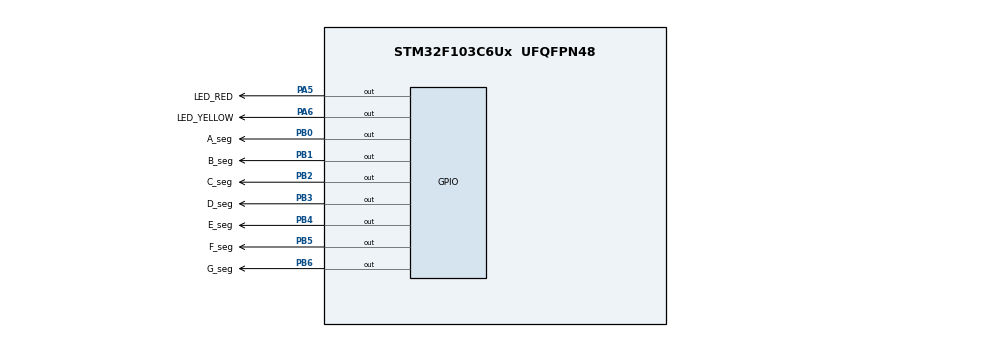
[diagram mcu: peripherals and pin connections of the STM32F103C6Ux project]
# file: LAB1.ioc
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Mcu.Family=STM32F1
Mcu.Name=STM32F103C6Ux
Mcu.Package=UFQFPN48
NVIC.PriorityGroup=NVIC_PRIORITYGROUP_4
PA5.GPIO_Label=LED_RED
PA5.Signal=GPIO_Output
PA6.GPIO_Label=LED_YELLOW
PA6.Signal=GPIO_Output
PB0.GPIO_Label=A_seg
PB0.Signal=GPIO_Output
PB1.GPIO_Label=B_seg
PB1.Signal=GPIO_Output
PB2.GPIO_Label=C_seg
PB2.Signal=GPIO_Output
PB3.GPIO_Label=D_seg
PB3.Signal=GPIO_Output
PB4.GPIO_Label=E_seg
PB4.Signal=GPIO_Output
PB5.GPIO_Label=F_seg
PB5.Signal=GPIO_Output
PB6.GPIO_Label=G_seg
PB6.Signal=GPIO_Output
ProjectManager.HeapSize=0x200
ProjectManager.StackSize=0x400
ProjectManager.TargetToolchain=STM32CubeIDE
RCC.APB1Freq_Value=8000000
RCC.APB2Freq_Value=8000000
VP_SYS_VS_ND.Mode=No_Debug
board=custom

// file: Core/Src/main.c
/* USER CODE BEGIN Header */
/**
  ******************************************************************************
  * @file           : main.c
  * @brief          : Main program body
  ******************************************************************************
  * @attention
  *
  * <h2><center>&copy; Copyright (c) 2023 STMicroelectronics.
  * All rights reserved.</center></h2>
  *
  * This software component is licensed by ST under BSD 3-Clause license,
  * the "License"; You may not use this file except in compliance with the
  * License. You may obtain a copy of the License at:
  *                        opensource.org/licenses/BSD-3-Clause
  *
  ******************************************************************************
  */
/* USER CODE END Header */
#include "main.h"

void SystemClock_Config(void);
static void MX_GPIO_Init(void);
/* USER CODE BEGIN PFP */
void setNumberOnClock(int counter,
		GPIO_TypeDef* C1_GPIO_Post, uint16_t C1_GPIO_Pin,
		GPIO_TypeDef* C2_GPIO_Post, uint16_t C2_GPIO_Pin,
		GPIO_TypeDef* C3_GPIO_Post, uint16_t C3_GPIO_Pin,
		GPIO_TypeDef* C4_GPIO_Post, uint16_t C4_GPIO_Pin,
		GPIO_TypeDef* C5_GPIO_Post, uint16_t C5_GPIO_Pin,
		GPIO_TypeDef* C6_GPIO_Post, uint16_t C6_GPIO_Pin,
		GPIO_TypeDef* C7_GPIO_Post, uint16_t C7_GPIO_Pin,
		GPIO_TypeDef* C8_GPIO_Post, uint16_t C8_GPIO_Pin,
		GPIO_TypeDef* C9_GPIO_Post, uint16_t C9_GPIO_Pin,
		GPIO_TypeDef* C10_GPIO_Post, uint16_t C10_GPIO_Pin,
		GPIO_TypeDef* C11_GPIO_Post, uint16_t C11_GPIO_Pin,
		GPIO_TypeDef* C12_GPIO_Post, uint16_t C12_GPIO_Pin
		){
	switch(counter){
	case 1:
		HAL_GPIO_WritePin(C1_GPIO_Post, C1_GPIO_Pin, SET);
		break;
	case 2:
		HAL_GPIO_WritePin(C2_GPIO_Post, C2_GPIO_Pin, SET);
		break;
	case 3:
		HAL_GPIO_WritePin(C3_GPIO_Post, C3_GPIO_Pin, SET);
		break;
	case 4:
		HAL_GPIO_WritePin(C4_GPIO_Post, C4_GPIO_Pin, SET);
		break;
	case 5:
		HAL_GPIO_WritePin(C5_GPIO_Post, C5_GPIO_Pin, SET);
		break;
	case 6:
		HAL_GPIO_WritePin(C6_GPIO_Post, C6_GPIO_Pin, SET);
		break;
	case 7:
		HAL_GPIO_WritePin(C7_GPIO_Post, C7_GPIO_Pin, SET);
		break;
	case 8:
		HAL_GPIO_WritePin(C8_GPIO_Post, C8_GPIO_Pin, SET);
		break;
	case 9:
		HAL_GPIO_WritePin(C9_GPIO_Post, C9_GPIO_Pin, SET);
		break;
	case 10:
		HAL_GPIO_WritePin(C10_GPIO_Post, C10_GPIO_Pin, SET);
		break;
	case 11:
		HAL_GPIO_WritePin(C11_GPIO_Post, C11_GPIO_Pin, SET);
		break;
	case 12:
		HAL_GPIO_WritePin(C12_GPIO_Post, C12_GPIO_Pin, SET);
		break;
	default:
		break;
	};
}

void clearNumberOnClock(int counter,
		GPIO_TypeDef* C1_GPIO_Post, uint16_t C1_GPIO_Pin,
		GPIO_TypeDef* C2_GPIO_Post, uint16_t C2_GPIO_Pin,
		GPIO_TypeDef* C3_GPIO_Post, uint16_t C3_GPIO_Pin,
		GPIO_TypeDef* C4_GPIO_Post, uint16_t C4_GPIO_Pin,
		GPIO_TypeDef* C5_GPIO_Post, uint16_t C5_GPIO_Pin,
		GPIO_TypeDef* C6_GPIO_Post, uint16_t C6_GPIO_Pin,
		GPIO_TypeDef* C7_GPIO_Post, uint16_t C7_GPIO_Pin,
		GPIO_TypeDef* C8_GPIO_Post, uint16_t C8_GPIO_Pin,
		GPIO_TypeDef* C9_GPIO_Post, uint16_t C9_GPIO_Pin,
		GPIO_TypeDef* C10_GPIO_Post, uint16_t C10_GPIO_Pin,
		GPIO_TypeDef* C11_GPIO_Post, uint16_t C11_GPIO_Pin,
		GPIO_TypeDef* C12_GPIO_Post, uint16_t C12_GPIO_Pin
		){
	switch(counter){
	case 1:
		HAL_GPIO_WritePin(C1_GPIO_Post, C1_GPIO_Pin, RESET);
		break;
	case 2:
		HAL_GPIO_WritePin(C2_GPIO_Post, C2_GPIO_Pin, RESET);
		break;
	case 3:
		HAL_GPIO_WritePin(C3_GPIO_Post, C3_GPIO_Pin, RESET);
		break;
	case 4:
		HAL_GPIO_WritePin(C4_GPIO_Post, C4_GPIO_Pin, RESET);
		break;
	case 5:
		HAL_GPIO_WritePin(C5_GPIO_Post, C5_GPIO_Pin, RESET);
		break;
	case 6:
		HAL_GPIO_WritePin(C6_GPIO_Post, C6_GPIO_Pin, RESET);
		break;
	case 7:
		HAL_GPIO_WritePin(C7_GPIO_Post, C7_GPIO_Pin, RESET);
		break;
	case 8:
		HAL_GPIO_WritePin(C8_GPIO_Post, C8_GPIO_Pin, RESET);
		break;
	case 9:
		HAL_GPIO_WritePin(C9_GPIO_Post, C9_GPIO_Pin, RESET);
		break;
	case 10:
		HAL_GPIO_WritePin(C10_GPIO_Post, C10_GPIO_Pin, RESET);
		break;
	case 11:
		HAL_GPIO_WritePin(C11_GPIO_Post, C11_GPIO_Pin, RESET);
		break;
	case 12:
		HAL_GPIO_WritePin(C12_GPIO_Post, C12_GPIO_Pin, RESET);
		break;
	default:
		break;
	};
}

/* USER CODE END PFP */

int main(void)
{

  /* MCU Configuration--------------------------------------------------------*/

  /* Reset of all peripherals, Initializes the Flash interface and the Systick. */
  HAL_Init();

  /* Configure the system clock */
  SystemClock_Config();

  /* Initialize all configured peripherals */
  MX_GPIO_Init();

  /* Infinite loop */
  /* USER CODE BEGIN WHILE */
	int counter = 0 ;
	int min = 0;
	int hour = 0;
	int sec = 0;
  while (1)
  {
	  counter ++;
		if (counter%60 == 0 ){
			sec = 0;
			min ++;
		}
		if (min%60 == 0){
			min = 0 ;
			hour ++;
		}
		clearNumberOnClock ((sec-1)%5,
				C1_GPIO_Port, C1_Pin,
									  		  				C2_GPIO_Port, C2_Pin,
									  		  				C3_GPIO_Port, C3_Pin,
									  		  				C4_GPIO_Port, C4_Pin,
									  		  				C5_GPIO_Port, C5_Pin,
									  		  				C6_GPIO_Port, C6_Pin,
									  		  				C7_GPIO_Port, C7_Pin,
									  		  				C8_GPIO_Port, C8_Pin,
									  		  				C9_GPIO_Port, C9_Pin,
									  		  				C10_GPIO_Port, C10_Pin,
									  		  				C11_GPIO_Port, C11_Pin,
									  		  				C12_GPIO_Port, C12_Pin);

		setNumberOnClock(sec%5,
							  	  	  	  	C1_GPIO_Port, C1_Pin,
					  		  				C2_GPIO_Port, C2_Pin,
					  		  				C3_GPIO_Port, C3_Pin,
					  		  				C4_GPIO_Port, C4_Pin,
					  		  				C5_GPIO_Port, C5_Pin,
					  		  				C6_GPIO_Port, C6_Pin,
					  		  				C7_GPIO_Port, C7_Pin,
					  		  				C8_GPIO_Port, C8_Pin,
					  		  				C9_GPIO_Port, C9_Pin,
					  		  				C10_GPIO_Port, C10_Pin,
					  		  				C11_GPIO_Port, C11_Pin,
					  		  				C12_GPIO_Port, C12_Pin);
		setNumberOnClock(min%5,
								  	  	  	  	C1_GPIO_Port, C1_Pin,
						  		  				C2_GPIO_Port, C2_Pin,
						  		  				C3_GPIO_Port, C3_Pin,
						  		  				C4_GPIO_Port, C4_Pin,
						  		  				C5_GPIO_Port, C5_Pin,
						  		  				C6_GPIO_Port, C6_Pin,
						  		  				C7_GPIO_Port, C7_Pin,
						  		  				C8_GPIO_Port, C8_Pin,
						  		  				C9_GPIO_Port, C9_Pin,
						  		  				C10_GPIO_Port, C10_Pin,
						  		  				C11_GPIO_Port, C11_Pin,
						  		  				C12_GPIO_Port, C12_Pin);
		setNumberOnClock(hour%5,
								  	  	  	  	C1_GPIO_Port, C1_Pin,
						  		  				C2_GPIO_Port, C2_Pin,
						  		  				C3_GPIO_Port, C3_Pin,
						  		  				C4_GPIO_Port, C4_Pin,
						  		  				C5_GPIO_Port, C5_Pin,
						  		  				C6_GPIO_Port, C6_Pin,
						  		  				C7_GPIO_Port, C7_Pin,
						  		  				C8_GPIO_Port, C8_Pin,
						  		  				C9_GPIO_Port, C9_Pin,
						  		  				C10_GPIO_Port, C10_Pin,
						  		  				C11_GPIO_Port, C11_Pin,
						  		  				C12_GPIO_Port, C12_Pin);

		HAL_Delay(1000);

    /* USER CODE END WHILE */

  }
}

void SystemClock_Config(void)
{
  RCC_OscInitTypeDef RCC_OscInitStruct = {0};
  RCC_ClkInitTypeDef RCC_ClkInitStruct = {0};

  /** Initializes the RCC Oscillators according to the specified parameters
  * in the RCC_OscInitTypeDef structure.
  */
  RCC_OscInitStruct.OscillatorType = RCC_OSCILLATORTYPE_HSI;
  RCC_OscInitStruct.HSIState = RCC_HSI_ON;
  RCC_OscInitStruct.HSICalibrationValue = RCC_HSICALIBRATION_DEFAULT;
  RCC_OscInitStruct.PLL.PLLState = RCC_PLL_NONE;
  if (HAL_RCC_OscConfig(&RCC_OscInitStruct) != HAL_OK)
  {
    Error_Handler();
  }
  /** Initializes the CPU, AHB and APB buses clocks
  */
  RCC_ClkInitStruct.ClockType = RCC_CLOCKTYPE_HCLK|RCC_CLOCKTYPE_SYSCLK
                              |RCC_CLOCKTYPE_PCLK1|RCC_CLOCKTYPE_PCLK2;
  RCC_ClkInitStruct.SYSCLKSource = RCC_SYSCLKSOURCE_HSI;
  RCC_ClkInitStruct.AHBCLKDivider = RCC_SYSCLK_DIV1;
  RCC_ClkInitStruct.APB1CLKDivider = RCC_HCLK_DIV1;
  RCC_ClkInitStruct.APB2CLKDivider = RCC_HCLK_DIV1;

  if (HAL_RCC_ClockConfig(&RCC_ClkInitStruct, FLASH_LATENCY_0) != HAL_OK)
  {
    Error_Handler();
  }
}

static void MX_GPIO_Init(void)
{
  GPIO_InitTypeDef GPIO_InitStruct = {0};

  /* GPIO Ports Clock Enable */
  __HAL_RCC_GPIOA_CLK_ENABLE();

  /*Configure GPIO pin Output Level */
  HAL_GPIO_WritePin(GPIOA, C1_Pin|C2_Pin|C3_Pin|C4_Pin
                          |C5_Pin|C6_Pin|C7_Pin|C8_Pin
                          |C9_Pin|C10_Pin|C11_Pin|C12_Pin, GPIO_PIN_RESET);

  /*Configure GPIO pins : C1_Pin C2_Pin C3_Pin C4_Pin
                           C5_Pin C6_Pin C7_Pin C8_Pin
                           C9_Pin C10_Pin C11_Pin C12_Pin */
  GPIO_InitStruct.Pin = C1_Pin|C2_Pin|C3_Pin|C4_Pin
                          |C5_Pin|C6_Pin|C7_Pin|C8_Pin
                          |C9_Pin|C10_Pin|C11_Pin|C12_Pin;
  GPIO_InitStruct.Mode = GPIO_MODE_OUTPUT_PP;
  GPIO_InitStruct.Pull = GPIO_NOPULL;
  GPIO_InitStruct.Speed = GPIO_SPEED_FREQ_LOW;
  HAL_GPIO_Init(GPIOA, &GPIO_InitStruct);

}

void Error_Handler(void)
{
  __disable_irq();
  while (1)
  {
  }
}

/************************ (C) COPYRIGHT STMicroelectronics *****END OF FILE****/
